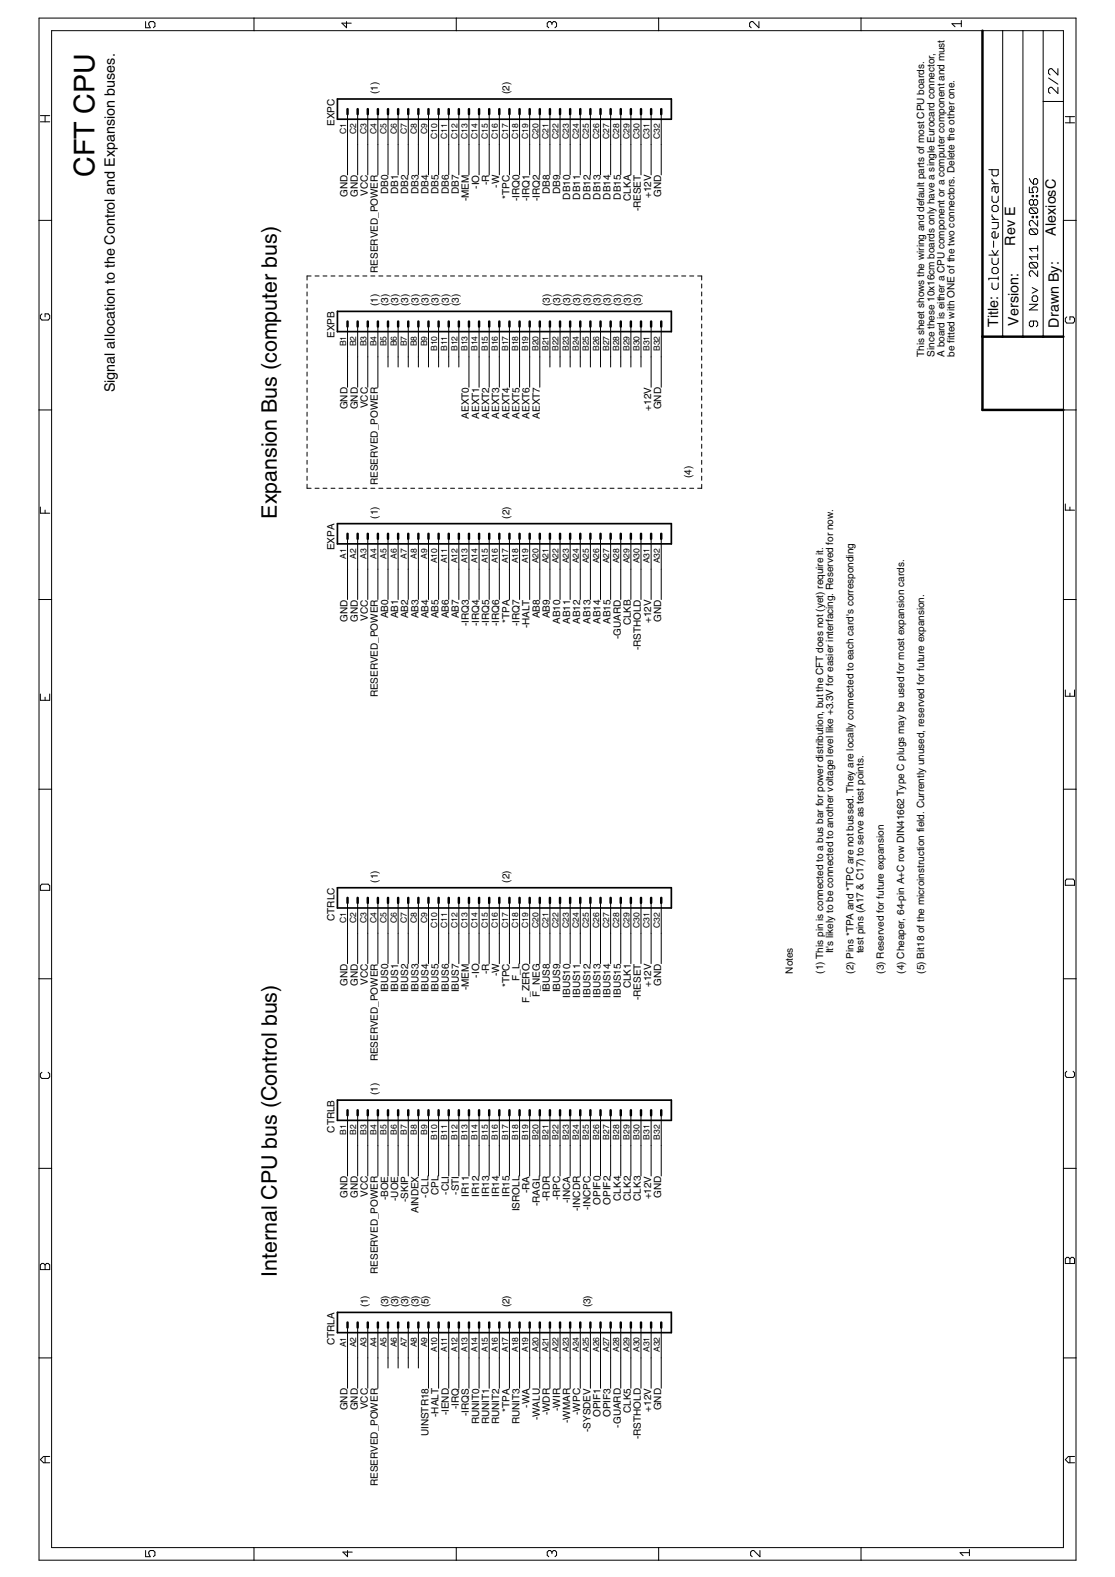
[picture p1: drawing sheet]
<svg xmlns="http://www.w3.org/2000/svg" width="210mm" height="297mm" viewBox="0 0 210 297" stroke-linecap="round" stroke-linejoin="round" font-family="sans-serif">
<defs><g id="words">
<text font-size="5.4" x="17.8" y="33.3" transform="rotate(-90 17.8 33.3)">CFT CPU</text>
<g font-size="4">
<text x="52.1" y="97.7" transform="rotate(-90 52.1 97.7)">Expansion Bus (computer bus)</text>
<text x="52.1" y="240.5" transform="rotate(-90 52.1 240.5)">Internal CPU bus (Control bus)</text>
</g>
<g font-size="2.7">
<text x="191.1" y="46.3" transform="rotate(-90 191.1 46.3)">Rev E</text>
<text x="198.8" y="44.4" transform="rotate(-90 198.8 44.4)">AlexiosC</text>
<text x="187.9" y="61.5" transform="rotate(-90 187.9 61.5)">Title:</text>
<text x="191.7" y="61.3" transform="rotate(-90 191.7 61.3)">Version:</text>
<text x="199.3" y="61.7" transform="rotate(-90 199.3 61.7)">Drawn By:</text>
<text x="21.6" y="73.9" transform="rotate(-90 21.6 73.9)">Signal allocation to the Control and Expansion buses.</text>
</g>
<g font-size="1.9">
<text x="71.1" y="17.7" transform="rotate(-90 71.1 17.7)">(1)</text>
<text x="95.9" y="17.7" transform="rotate(-90 95.9 17.7)">(2)</text>
<text x="63" y="23.7" transform="rotate(-90 63 23.7)">EXPC</text>
<text x="90.2" y="35.6" transform="rotate(-90 90.2 35.6)">-IO</text>
<text x="92.1" y="34.9" transform="rotate(-90 92.1 34.9)">-R</text>
<text x="94" y="35.3" transform="rotate(-90 94 35.3)">-W</text>
<text x="65.4" y="37.1" transform="rotate(-90 65.4 37.1)">GND</text>
<text x="67.3" y="37.1" transform="rotate(-90 67.3 37.1)">GND</text>
<text x="69.2" y="36.9" transform="rotate(-90 69.2 36.9)">VCC</text>
<text x="73" y="36.6" transform="rotate(-90 73 36.6)">DB0</text>
<text x="75" y="36.6" transform="rotate(-90 75 36.6)">DB1</text>
<text x="76.9" y="36.6" transform="rotate(-90 76.9 36.6)">DB2</text>
<text x="78.8" y="36.6" transform="rotate(-90 78.8 36.6)">DB3</text>
<text x="80.7" y="36.6" transform="rotate(-90 80.7 36.6)">DB4</text>
<text x="82.6" y="36.6" transform="rotate(-90 82.6 36.6)">DB5</text>
<text x="84.5" y="36.6" transform="rotate(-90 84.5 36.6)">DB6</text>
<text x="86.4" y="36.6" transform="rotate(-90 86.4 36.6)">DB7</text>
<text x="88.3" y="37.9" transform="rotate(-90 88.3 37.9)">-MEM</text>
<text x="95.9" y="37.4" transform="rotate(-90 95.9 37.4)">*TPC</text>
<text x="97.8" y="37.9" transform="rotate(-90 97.8 37.9)">-IRQ0</text>
<text x="99.7" y="37.9" transform="rotate(-90 99.7 37.9)">-IRQ1</text>
<text x="101.6" y="37.9" transform="rotate(-90 101.6 37.9)">-IRQ2</text>
<text x="103.5" y="36.6" transform="rotate(-90 103.5 36.6)">DB8</text>
<text x="105.4" y="36.6" transform="rotate(-90 105.4 36.6)">DB9</text>
<text x="107.3" y="37.6" transform="rotate(-90 107.3 37.6)">DB10</text>
<text x="109.2" y="37.6" transform="rotate(-90 109.2 37.6)">DB11</text>
<text x="111.1" y="37.6" transform="rotate(-90 111.1 37.6)">DB12</text>
<text x="113" y="37.6" transform="rotate(-90 113 37.6)">DB13</text>
<text x="114.9" y="37.6" transform="rotate(-90 114.9 37.6)">DB14</text>
<text x="116.9" y="37.6" transform="rotate(-90 116.9 37.6)">DB15</text>
<text x="118.8" y="37.8" transform="rotate(-90 118.8 37.8)">CLKA</text>
<text x="120.7" y="39.8" transform="rotate(-90 120.7 39.8)">-RESET</text>
<text x="122.6" y="37.4" transform="rotate(-90 122.6 37.4)">+12V</text>
<text x="124.5" y="37.1" transform="rotate(-90 124.5 37.1)">GND</text>
<text x="71.1" y="51.4" transform="rotate(-90 71.1 51.4)">RESERVED_POWER</text>
<text x="71.1" y="57.7" transform="rotate(-90 71.1 57.7)">(1)</text>
<text x="73" y="57.7" transform="rotate(-90 73 57.7)">(3)</text>
<text x="75" y="57.7" transform="rotate(-90 75 57.7)">(3)</text>
<text x="76.9" y="57.7" transform="rotate(-90 76.9 57.7)">(3)</text>
<text x="78.8" y="57.7" transform="rotate(-90 78.8 57.7)">(3)</text>
<text x="80.7" y="57.7" transform="rotate(-90 80.7 57.7)">(3)</text>
<text x="82.6" y="57.7" transform="rotate(-90 82.6 57.7)">(3)</text>
<text x="84.5" y="57.7" transform="rotate(-90 84.5 57.7)">(3)</text>
<text x="86.4" y="57.7" transform="rotate(-90 86.4 57.7)">(3)</text>
<text x="103.5" y="57.7" transform="rotate(-90 103.5 57.7)">(3)</text>
<text x="105.4" y="57.7" transform="rotate(-90 105.4 57.7)">(3)</text>
<text x="107.3" y="57.7" transform="rotate(-90 107.3 57.7)">(3)</text>
<text x="109.2" y="57.7" transform="rotate(-90 109.2 57.7)">(3)</text>
<text x="111.1" y="57.7" transform="rotate(-90 111.1 57.7)">(3)</text>
<text x="113" y="57.7" transform="rotate(-90 113 57.7)">(3)</text>
<text x="114.9" y="57.7" transform="rotate(-90 114.9 57.7)">(3)</text>
<text x="116.9" y="57.7" transform="rotate(-90 116.9 57.7)">(3)</text>
<text x="118.8" y="57.7" transform="rotate(-90 118.8 57.7)">(3)</text>
<text x="120.7" y="57.7" transform="rotate(-90 120.7 57.7)">(3)</text>
<text x="63" y="63.6" transform="rotate(-90 63 63.6)">EXPB</text>
<text x="174" y="67.2" transform="rotate(-90 174 67.2)">This sheet shows the wiring and default parts of most CPU boards.</text>
<text x="175.9" y="67.2" transform="rotate(-90 175.9 67.2)">Since these 10x16cm boards only have a single Eurocard connector,</text>
<text x="177.8" y="67.2" transform="rotate(-90 177.8 67.2)">A board is either a CPU component or a computer component and must</text>
<text x="179.7" y="67.2" transform="rotate(-90 179.7 67.2)">be fitted with ONE of the two connectors. Delete the other one.</text>
<text x="65.4" y="77.1" transform="rotate(-90 65.4 77.1)">GND</text>
<text x="67.3" y="77.1" transform="rotate(-90 67.3 77.1)">GND</text>
<text x="69.2" y="76.9" transform="rotate(-90 69.2 76.9)">VCC</text>
<text x="122.6" y="77.4" transform="rotate(-90 122.6 77.4)">+12V</text>
<text x="124.5" y="77.1" transform="rotate(-90 124.5 77.1)">GND</text>
<text x="88.3" y="78.9" transform="rotate(-90 88.3 78.9)">AEXT0</text>
<text x="90.2" y="78.9" transform="rotate(-90 90.2 78.9)">AEXT1</text>
<text x="92.1" y="78.9" transform="rotate(-90 92.1 78.9)">AEXT2</text>
<text x="94" y="78.9" transform="rotate(-90 94 78.9)">AEXT3</text>
<text x="95.9" y="78.9" transform="rotate(-90 95.9 78.9)">AEXT4</text>
<text x="97.8" y="78.9" transform="rotate(-90 97.8 78.9)">AEXT5</text>
<text x="99.7" y="78.9" transform="rotate(-90 99.7 78.9)">AEXT6</text>
<text x="101.6" y="78.9" transform="rotate(-90 101.6 78.9)">AEXT7</text>
<text x="71.1" y="91.4" transform="rotate(-90 71.1 91.4)">RESERVED_POWER</text>
<text x="130.2" y="90.1" transform="rotate(-90 130.2 90.1)">(4)</text>
<text x="71.1" y="97.7" transform="rotate(-90 71.1 97.7)">(1)</text>
<text x="95.9" y="97.7" transform="rotate(-90 95.9 97.7)">(2)</text>
<text x="63" y="103.6" transform="rotate(-90 63 103.6)">EXPA</text>
<text x="65.4" y="117.1" transform="rotate(-90 65.4 117.1)">GND</text>
<text x="67.3" y="117.1" transform="rotate(-90 67.3 117.1)">GND</text>
<text x="69.2" y="116.9" transform="rotate(-90 69.2 116.9)">VCC</text>
<text x="73" y="116.5" transform="rotate(-90 73 116.5)">AB0</text>
<text x="75" y="116.5" transform="rotate(-90 75 116.5)">AB1</text>
<text x="76.9" y="116.5" transform="rotate(-90 76.9 116.5)">AB2</text>
<text x="78.8" y="116.5" transform="rotate(-90 78.8 116.5)">AB3</text>
<text x="80.7" y="116.5" transform="rotate(-90 80.7 116.5)">AB4</text>
<text x="82.6" y="116.5" transform="rotate(-90 82.6 116.5)">AB5</text>
<text x="84.5" y="116.5" transform="rotate(-90 84.5 116.5)">AB6</text>
<text x="86.4" y="116.5" transform="rotate(-90 86.4 116.5)">AB7</text>
<text x="88.3" y="117.9" transform="rotate(-90 88.3 117.9)">-IRQ3</text>
<text x="90.2" y="117.9" transform="rotate(-90 90.2 117.9)">-IRQ4</text>
<text x="92.1" y="117.9" transform="rotate(-90 92.1 117.9)">-IRQ5</text>
<text x="94" y="117.9" transform="rotate(-90 94 117.9)">-IRQ6</text>
<text x="95.9" y="117.3" transform="rotate(-90 95.9 117.3)">*TPA</text>
<text x="97.8" y="117.9" transform="rotate(-90 97.8 117.9)">-IRQ7</text>
<text x="99.7" y="118.3" transform="rotate(-90 99.7 118.3)">-HALT</text>
<text x="101.6" y="116.5" transform="rotate(-90 101.6 116.5)">AB8</text>
<text x="103.5" y="116.5" transform="rotate(-90 103.5 116.5)">AB9</text>
<text x="105.4" y="117.5" transform="rotate(-90 105.4 117.5)">AB10</text>
<text x="107.3" y="117.5" transform="rotate(-90 107.3 117.5)">AB11</text>
<text x="109.2" y="117.5" transform="rotate(-90 109.2 117.5)">AB12</text>
<text x="111.1" y="117.5" transform="rotate(-90 111.1 117.5)">AB13</text>
<text x="113" y="117.5" transform="rotate(-90 113 117.5)">AB14</text>
<text x="114.9" y="117.5" transform="rotate(-90 114.9 117.5)">AB15</text>
<text x="118.8" y="117.8" transform="rotate(-90 118.8 117.8)">CLKB</text>
<text x="122.6" y="117.4" transform="rotate(-90 122.6 117.4)">+12V</text>
<text x="124.5" y="117.1" transform="rotate(-90 124.5 117.1)">GND</text>
<text x="116.9" y="120.3" transform="rotate(-90 116.9 120.3)">-GUARD</text>
<text x="120.7" y="122.5" transform="rotate(-90 120.7 122.5)">-RSTHOLD</text>
<text x="71.1" y="131.4" transform="rotate(-90 71.1 131.4)">RESERVED_POWER</text>
<text x="71.1" y="166.3" transform="rotate(-90 71.1 166.3)">(1)</text>
<text x="95.9" y="166.3" transform="rotate(-90 95.9 166.3)">(2)</text>
<text x="63" y="173.5" transform="rotate(-90 63 173.5)">CTRLC</text>
<text x="156.9" y="179.6" transform="rotate(-90 156.9 179.6)">It's likely to be connected to another voltage level like +3.3V for easier interfacing. Reserved for now.</text>
<text x="162.6" y="179.6" transform="rotate(-90 162.6 179.6)">test pins (A17 &amp; C17) to serve as test points.</text>
<text x="65.4" y="185.7" transform="rotate(-90 65.4 185.7)">GND</text>
<text x="67.3" y="185.7" transform="rotate(-90 67.3 185.7)">GND</text>
<text x="69.2" y="185.5" transform="rotate(-90 69.2 185.5)">VCC</text>
<text x="90.2" y="184.1" transform="rotate(-90 90.2 184.1)">-IO</text>
<text x="92.1" y="183.5" transform="rotate(-90 92.1 183.5)">-R</text>
<text x="94" y="183.9" transform="rotate(-90 94 183.9)">-W</text>
<text x="95.9" y="186" transform="rotate(-90 95.9 186)">*TPC</text>
<text x="97.8" y="184.7" transform="rotate(-90 97.8 184.7)">F_L</text>
<text x="122.6" y="185.9" transform="rotate(-90 122.6 185.9)">+12V</text>
<text x="124.5" y="185.7" transform="rotate(-90 124.5 185.7)">GND</text>
<text x="149.2" y="183.4" transform="rotate(-90 149.2 183.4)">Notes</text>
<text x="154.9" y="183.4" transform="rotate(-90 154.9 183.4)">(1) This pin is connected to a bus bar for power distribution, but the CFT does not (yet) require it.</text>
<text x="160.7" y="183.4" transform="rotate(-90 160.7 183.4)">(2) Pins *TPA and *TPC are not bussed. They are locally connected to each card's corresponding</text>
<text x="166.4" y="183.4" transform="rotate(-90 166.4 183.4)">(3) Reserved for future expansion</text>
<text x="170.2" y="183.4" transform="rotate(-90 170.2 183.4)">(4) Cheaper, 64-pin A+C row DIN41662 Type C plugs may be used for most expansion cards.</text>
<text x="174" y="183.4" transform="rotate(-90 174 183.4)">(5) Bit18 of the microinstruction field. Currently unused, reserved for future expansion.</text>
<text x="73" y="186.9" transform="rotate(-90 73 186.9)">IBUS0</text>
<text x="75" y="186.9" transform="rotate(-90 75 186.9)">IBUS1</text>
<text x="76.9" y="186.9" transform="rotate(-90 76.9 186.9)">IBUS2</text>
<text x="78.8" y="186.9" transform="rotate(-90 78.8 186.9)">IBUS3</text>
<text x="80.7" y="186.9" transform="rotate(-90 80.7 186.9)">IBUS4</text>
<text x="82.6" y="186.9" transform="rotate(-90 82.6 186.9)">IBUS5</text>
<text x="84.5" y="186.9" transform="rotate(-90 84.5 186.9)">IBUS6</text>
<text x="86.4" y="186.9" transform="rotate(-90 86.4 186.9)">IBUS7</text>
<text x="88.3" y="186.5" transform="rotate(-90 88.3 186.5)">-MEM</text>
<text x="99.7" y="188.9" transform="rotate(-90 99.7 188.9)">F_ZERO</text>
<text x="101.6" y="187.7" transform="rotate(-90 101.6 187.7)">F_NEG</text>
<text x="103.5" y="186.9" transform="rotate(-90 103.5 186.9)">IBUS8</text>
<text x="105.4" y="186.9" transform="rotate(-90 105.4 186.9)">IBUS9</text>
<text x="107.3" y="188" transform="rotate(-90 107.3 188)">IBUS10</text>
<text x="109.2" y="188" transform="rotate(-90 109.2 188)">IBUS11</text>
<text x="111.1" y="188" transform="rotate(-90 111.1 188)">IBUS12</text>
<text x="113" y="188" transform="rotate(-90 113 188)">IBUS13</text>
<text x="114.9" y="188" transform="rotate(-90 114.9 188)">IBUS14</text>
<text x="116.9" y="188" transform="rotate(-90 116.9 188)">IBUS15</text>
<text x="118.8" y="186.2" transform="rotate(-90 118.8 186.2)">CLK1</text>
<text x="120.7" y="188.4" transform="rotate(-90 120.7 188.4)">-RESET</text>
<text x="71.1" y="199.9" transform="rotate(-90 71.1 199.9)">RESERVED_POWER</text>
<text x="71.1" y="206.3" transform="rotate(-90 71.1 206.3)">(1)</text>
<text x="63" y="213.3" transform="rotate(-90 63 213.3)">CTRLB</text>
<text x="65.4" y="225.7" transform="rotate(-90 65.4 225.7)">GND</text>
<text x="67.3" y="225.7" transform="rotate(-90 67.3 225.7)">GND</text>
<text x="69.2" y="225.5" transform="rotate(-90 69.2 225.5)">VCC</text>
<text x="73" y="226.1" transform="rotate(-90 73 226.1)">-BOE</text>
<text x="75" y="226.2" transform="rotate(-90 75 226.2)">-UOE</text>
<text x="76.9" y="226.4" transform="rotate(-90 76.9 226.4)">-SKIP</text>
<text x="80.7" y="225.6" transform="rotate(-90 80.7 225.6)">-CLL</text>
<text x="82.6" y="225.1" transform="rotate(-90 82.6 225.1)">CPL</text>
<text x="84.5" y="225.1" transform="rotate(-90 84.5 225.1)">-CLI</text>
<text x="86.4" y="225.1" transform="rotate(-90 86.4 225.1)">-STI</text>
<text x="88.3" y="225.5" transform="rotate(-90 88.3 225.5)">IR11</text>
<text x="90.2" y="225.5" transform="rotate(-90 90.2 225.5)">IR12</text>
<text x="92.1" y="225.5" transform="rotate(-90 92.1 225.5)">IR13</text>
<text x="94" y="225.5" transform="rotate(-90 94 225.5)">IR14</text>
<text x="95.9" y="225.5" transform="rotate(-90 95.9 225.5)">IR15</text>
<text x="99.7" y="224.7" transform="rotate(-90 99.7 224.7)">-RA</text>
<text x="101.6" y="227.2" transform="rotate(-90 101.6 227.2)">-RAGL</text>
<text x="103.5" y="226.2" transform="rotate(-90 103.5 226.2)">-RDR</text>
<text x="105.4" y="226.1" transform="rotate(-90 105.4 226.1)">-RPC</text>
<text x="107.3" y="226.6" transform="rotate(-90 107.3 226.6)">-INCA</text>
<text x="111.1" y="228" transform="rotate(-90 111.1 228)">-INCPC</text>
<text x="113" y="226.9" transform="rotate(-90 113 226.9)">OPIF0</text>
<text x="114.9" y="226.9" transform="rotate(-90 114.9 226.9)">OPIF2</text>
<text x="116.9" y="226.2" transform="rotate(-90 116.9 226.2)">CLK4</text>
<text x="118.8" y="226.2" transform="rotate(-90 118.8 226.2)">CLK2</text>
<text x="120.7" y="226.2" transform="rotate(-90 120.7 226.2)">CLK3</text>
<text x="122.6" y="225.9" transform="rotate(-90 122.6 225.9)">+12V</text>
<text x="124.5" y="225.7" transform="rotate(-90 124.5 225.7)">GND</text>
<text x="78.8" y="228.5" transform="rotate(-90 78.8 228.5)">AINDEX</text>
<text x="97.8" y="228.2" transform="rotate(-90 97.8 228.2)">ISROLL</text>
<text x="109.2" y="228.1" transform="rotate(-90 109.2 228.1)">-INCDR</text>
<text x="71.1" y="239.9" transform="rotate(-90 71.1 239.9)">RESERVED_POWER</text>
<text x="69.2" y="246.3" transform="rotate(-90 69.2 246.3)">(1)</text>
<text x="73" y="246.3" transform="rotate(-90 73 246.3)">(3)</text>
<text x="75" y="246.3" transform="rotate(-90 75 246.3)">(3)</text>
<text x="76.9" y="246.3" transform="rotate(-90 76.9 246.3)">(3)</text>
<text x="78.8" y="246.3" transform="rotate(-90 78.8 246.3)">(3)</text>
<text x="80.7" y="246.3" transform="rotate(-90 80.7 246.3)">(5)</text>
<text x="95.9" y="246.3" transform="rotate(-90 95.9 246.3)">(2)</text>
<text x="111.1" y="246.3" transform="rotate(-90 111.1 246.3)">(3)</text>
<text x="63" y="253.3" transform="rotate(-90 63 253.3)">CTRLA</text>
<text x="65.4" y="265.7" transform="rotate(-90 65.4 265.7)">GND</text>
<text x="67.3" y="265.7" transform="rotate(-90 67.3 265.7)">GND</text>
<text x="69.2" y="265.5" transform="rotate(-90 69.2 265.5)">VCC</text>
<text x="82.6" y="266.9" transform="rotate(-90 82.6 266.9)">-HALT</text>
<text x="84.5" y="266.6" transform="rotate(-90 84.5 266.6)">-IEND</text>
<text x="86.4" y="265.5" transform="rotate(-90 86.4 265.5)">-IRQ</text>
<text x="88.3" y="266.7" transform="rotate(-90 88.3 266.7)">-IRQS</text>
<text x="90.2" y="268.3" transform="rotate(-90 90.2 268.3)">RUNIT0</text>
<text x="92.1" y="268.3" transform="rotate(-90 92.1 268.3)">RUNIT1</text>
<text x="94" y="268.3" transform="rotate(-90 94 268.3)">RUNIT2</text>
<text x="95.9" y="265.9" transform="rotate(-90 95.9 265.9)">*TPA</text>
<text x="97.8" y="268.3" transform="rotate(-90 97.8 268.3)">RUNIT3</text>
<text x="99.7" y="265.2" transform="rotate(-90 99.7 265.2)">-WA</text>
<text x="101.6" y="267.5" transform="rotate(-90 101.6 267.5)">-WALU</text>
<text x="103.5" y="266.6" transform="rotate(-90 103.5 266.6)">-WDR</text>
<text x="105.4" y="265.8" transform="rotate(-90 105.4 265.8)">-WIR</text>
<text x="107.3" y="268.1" transform="rotate(-90 107.3 268.1)">-WMAR</text>
<text x="109.2" y="266.5" transform="rotate(-90 109.2 266.5)">-WPC</text>
<text x="111.1" y="269.7" transform="rotate(-90 111.1 269.7)">-SYSDEV</text>
<text x="113" y="266.9" transform="rotate(-90 113 266.9)">OPIF1</text>
<text x="114.9" y="266.9" transform="rotate(-90 114.9 266.9)">OPIF3</text>
<text x="116.9" y="268.9" transform="rotate(-90 116.9 268.9)">-GUARD</text>
<text x="118.8" y="266.2" transform="rotate(-90 118.8 266.2)">CLK5</text>
<text x="122.6" y="265.9" transform="rotate(-90 122.6 265.9)">+12V</text>
<text x="124.5" y="265.7" transform="rotate(-90 124.5 265.7)">GND</text>
<text x="80.7" y="270.6" transform="rotate(-90 80.7 270.6)">UINSTR18</text>
<text x="120.7" y="271.1" transform="rotate(-90 120.7 271.1)">-RSTHOLD</text>
<text x="71.1" y="279.9" transform="rotate(-90 71.1 279.9)">RESERVED_POWER</text>
</g>
<g font-size="1.6">
<text x="65.2" y="25.3" transform="rotate(-90 65.2 25.3)">C1</text>
<text x="67.1" y="25.3" transform="rotate(-90 67.1 25.3)">C2</text>
<text x="69" y="25.3" transform="rotate(-90 69 25.3)">C3</text>
<text x="70.9" y="25.3" transform="rotate(-90 70.9 25.3)">C4</text>
<text x="72.8" y="25.3" transform="rotate(-90 72.8 25.3)">C5</text>
<text x="74.7" y="25.3" transform="rotate(-90 74.7 25.3)">C6</text>
<text x="76.6" y="25.3" transform="rotate(-90 76.6 25.3)">C7</text>
<text x="78.5" y="25.3" transform="rotate(-90 78.5 25.3)">C8</text>
<text x="80.4" y="25.3" transform="rotate(-90 80.4 25.3)">C9</text>
<text x="82.3" y="26.2" transform="rotate(-90 82.3 26.2)">C10</text>
<text x="84.2" y="26.2" transform="rotate(-90 84.2 26.2)">C11</text>
<text x="86.1" y="26.2" transform="rotate(-90 86.1 26.2)">C12</text>
<text x="88" y="26.2" transform="rotate(-90 88 26.2)">C13</text>
<text x="89.9" y="26.2" transform="rotate(-90 89.9 26.2)">C14</text>
<text x="91.8" y="26.2" transform="rotate(-90 91.8 26.2)">C15</text>
<text x="93.7" y="26.2" transform="rotate(-90 93.7 26.2)">C16</text>
<text x="95.6" y="26.2" transform="rotate(-90 95.6 26.2)">C17</text>
<text x="97.5" y="26.2" transform="rotate(-90 97.5 26.2)">C18</text>
<text x="99.4" y="26.2" transform="rotate(-90 99.4 26.2)">C19</text>
<text x="101.3" y="26.2" transform="rotate(-90 101.3 26.2)">C20</text>
<text x="103.3" y="26.2" transform="rotate(-90 103.3 26.2)">C21</text>
<text x="105.2" y="26.2" transform="rotate(-90 105.2 26.2)">C22</text>
<text x="107.1" y="26.2" transform="rotate(-90 107.1 26.2)">C23</text>
<text x="109" y="26.2" transform="rotate(-90 109 26.2)">C24</text>
<text x="110.9" y="26.2" transform="rotate(-90 110.9 26.2)">C25</text>
<text x="112.8" y="26.2" transform="rotate(-90 112.8 26.2)">C26</text>
<text x="114.7" y="26.2" transform="rotate(-90 114.7 26.2)">C27</text>
<text x="116.6" y="26.2" transform="rotate(-90 116.6 26.2)">C28</text>
<text x="118.5" y="26.2" transform="rotate(-90 118.5 26.2)">C29</text>
<text x="120.4" y="26.2" transform="rotate(-90 120.4 26.2)">C30</text>
<text x="122.3" y="26.2" transform="rotate(-90 122.3 26.2)">C31</text>
<text x="124.2" y="26.2" transform="rotate(-90 124.2 26.2)">C32</text>
<text x="65.2" y="65.2" transform="rotate(-90 65.2 65.2)">B1</text>
<text x="67.1" y="65.2" transform="rotate(-90 67.1 65.2)">B2</text>
<text x="69" y="65.2" transform="rotate(-90 69 65.2)">B3</text>
<text x="70.9" y="65.2" transform="rotate(-90 70.9 65.2)">B4</text>
<text x="72.8" y="65.2" transform="rotate(-90 72.8 65.2)">B5</text>
<text x="74.7" y="65.2" transform="rotate(-90 74.7 65.2)">B6</text>
<text x="76.6" y="65.2" transform="rotate(-90 76.6 65.2)">B7</text>
<text x="78.5" y="65.2" transform="rotate(-90 78.5 65.2)">B8</text>
<text x="80.4" y="65.2" transform="rotate(-90 80.4 65.2)">B9</text>
<text x="82.3" y="66.1" transform="rotate(-90 82.3 66.1)">B10</text>
<text x="84.2" y="66.1" transform="rotate(-90 84.2 66.1)">B11</text>
<text x="86.1" y="66.1" transform="rotate(-90 86.1 66.1)">B12</text>
<text x="88" y="66.1" transform="rotate(-90 88 66.1)">B13</text>
<text x="89.9" y="66.1" transform="rotate(-90 89.9 66.1)">B14</text>
<text x="91.8" y="66.1" transform="rotate(-90 91.8 66.1)">B15</text>
<text x="93.7" y="66.1" transform="rotate(-90 93.7 66.1)">B16</text>
<text x="95.6" y="66.1" transform="rotate(-90 95.6 66.1)">B17</text>
<text x="97.5" y="66.1" transform="rotate(-90 97.5 66.1)">B18</text>
<text x="99.4" y="66.1" transform="rotate(-90 99.4 66.1)">B19</text>
<text x="101.3" y="66.1" transform="rotate(-90 101.3 66.1)">B20</text>
<text x="103.3" y="66.1" transform="rotate(-90 103.3 66.1)">B21</text>
<text x="105.2" y="66.1" transform="rotate(-90 105.2 66.1)">B22</text>
<text x="107.1" y="66.1" transform="rotate(-90 107.1 66.1)">B23</text>
<text x="109" y="66.1" transform="rotate(-90 109 66.1)">B24</text>
<text x="110.9" y="66.1" transform="rotate(-90 110.9 66.1)">B25</text>
<text x="112.8" y="66.1" transform="rotate(-90 112.8 66.1)">B26</text>
<text x="114.7" y="66.1" transform="rotate(-90 114.7 66.1)">B27</text>
<text x="116.6" y="66.1" transform="rotate(-90 116.6 66.1)">B28</text>
<text x="118.5" y="66.1" transform="rotate(-90 118.5 66.1)">B29</text>
<text x="120.4" y="66.1" transform="rotate(-90 120.4 66.1)">B30</text>
<text x="122.3" y="66.1" transform="rotate(-90 122.3 66.1)">B31</text>
<text x="124.2" y="66.1" transform="rotate(-90 124.2 66.1)">B32</text>
<text x="65.2" y="105.2" transform="rotate(-90 65.2 105.2)">A1</text>
<text x="67.1" y="105.2" transform="rotate(-90 67.1 105.2)">A2</text>
<text x="69" y="105.2" transform="rotate(-90 69 105.2)">A3</text>
<text x="70.9" y="105.2" transform="rotate(-90 70.9 105.2)">A4</text>
<text x="72.8" y="105.2" transform="rotate(-90 72.8 105.2)">A5</text>
<text x="74.7" y="105.2" transform="rotate(-90 74.7 105.2)">A6</text>
<text x="76.6" y="105.2" transform="rotate(-90 76.6 105.2)">A7</text>
<text x="78.5" y="105.2" transform="rotate(-90 78.5 105.2)">A8</text>
<text x="80.4" y="105.2" transform="rotate(-90 80.4 105.2)">A9</text>
<text x="82.3" y="106.1" transform="rotate(-90 82.3 106.1)">A10</text>
<text x="84.2" y="106.1" transform="rotate(-90 84.2 106.1)">A11</text>
<text x="86.1" y="106.1" transform="rotate(-90 86.1 106.1)">A12</text>
<text x="88" y="106.1" transform="rotate(-90 88 106.1)">A13</text>
<text x="89.9" y="106.1" transform="rotate(-90 89.9 106.1)">A14</text>
<text x="91.8" y="106.1" transform="rotate(-90 91.8 106.1)">A15</text>
<text x="93.7" y="106.1" transform="rotate(-90 93.7 106.1)">A16</text>
<text x="95.6" y="106.1" transform="rotate(-90 95.6 106.1)">A17</text>
<text x="97.5" y="106.1" transform="rotate(-90 97.5 106.1)">A18</text>
<text x="99.4" y="106.1" transform="rotate(-90 99.4 106.1)">A19</text>
<text x="101.3" y="106.1" transform="rotate(-90 101.3 106.1)">A20</text>
<text x="103.3" y="106.1" transform="rotate(-90 103.3 106.1)">A21</text>
<text x="105.2" y="106.1" transform="rotate(-90 105.2 106.1)">A22</text>
<text x="107.1" y="106.1" transform="rotate(-90 107.1 106.1)">A23</text>
<text x="109" y="106.1" transform="rotate(-90 109 106.1)">A24</text>
<text x="110.9" y="106.1" transform="rotate(-90 110.9 106.1)">A25</text>
<text x="112.8" y="106.1" transform="rotate(-90 112.8 106.1)">A26</text>
<text x="114.7" y="106.1" transform="rotate(-90 114.7 106.1)">A27</text>
<text x="116.6" y="106.1" transform="rotate(-90 116.6 106.1)">A28</text>
<text x="118.5" y="106.1" transform="rotate(-90 118.5 106.1)">A29</text>
<text x="120.4" y="106.1" transform="rotate(-90 120.4 106.1)">A30</text>
<text x="122.3" y="106.1" transform="rotate(-90 122.3 106.1)">A31</text>
<text x="124.2" y="106.1" transform="rotate(-90 124.2 106.1)">A32</text>
<text x="65.2" y="173.9" transform="rotate(-90 65.2 173.9)">C1</text>
<text x="67.1" y="173.9" transform="rotate(-90 67.1 173.9)">C2</text>
<text x="69" y="173.9" transform="rotate(-90 69 173.9)">C3</text>
<text x="70.9" y="173.9" transform="rotate(-90 70.9 173.9)">C4</text>
<text x="72.8" y="173.9" transform="rotate(-90 72.8 173.9)">C5</text>
<text x="74.7" y="173.9" transform="rotate(-90 74.7 173.9)">C6</text>
<text x="76.6" y="173.9" transform="rotate(-90 76.6 173.9)">C7</text>
<text x="78.5" y="173.9" transform="rotate(-90 78.5 173.9)">C8</text>
<text x="80.4" y="173.9" transform="rotate(-90 80.4 173.9)">C9</text>
<text x="82.3" y="174.8" transform="rotate(-90 82.3 174.8)">C10</text>
<text x="84.2" y="174.8" transform="rotate(-90 84.2 174.8)">C11</text>
<text x="86.1" y="174.8" transform="rotate(-90 86.1 174.8)">C12</text>
<text x="88" y="174.8" transform="rotate(-90 88 174.8)">C13</text>
<text x="89.9" y="174.8" transform="rotate(-90 89.9 174.8)">C14</text>
<text x="91.8" y="174.8" transform="rotate(-90 91.8 174.8)">C15</text>
<text x="93.7" y="174.8" transform="rotate(-90 93.7 174.8)">C16</text>
<text x="95.6" y="174.8" transform="rotate(-90 95.6 174.8)">C17</text>
<text x="97.5" y="174.8" transform="rotate(-90 97.5 174.8)">C18</text>
<text x="99.4" y="174.8" transform="rotate(-90 99.4 174.8)">C19</text>
<text x="101.3" y="174.8" transform="rotate(-90 101.3 174.8)">C20</text>
<text x="103.3" y="174.8" transform="rotate(-90 103.3 174.8)">C21</text>
<text x="105.2" y="174.8" transform="rotate(-90 105.2 174.8)">C22</text>
<text x="107.1" y="174.8" transform="rotate(-90 107.1 174.8)">C23</text>
<text x="109" y="174.8" transform="rotate(-90 109 174.8)">C24</text>
<text x="110.9" y="174.8" transform="rotate(-90 110.9 174.8)">C25</text>
<text x="112.8" y="174.8" transform="rotate(-90 112.8 174.8)">C26</text>
<text x="114.7" y="174.8" transform="rotate(-90 114.7 174.8)">C27</text>
<text x="116.6" y="174.8" transform="rotate(-90 116.6 174.8)">C28</text>
<text x="118.5" y="174.8" transform="rotate(-90 118.5 174.8)">C29</text>
<text x="120.4" y="174.8" transform="rotate(-90 120.4 174.8)">C30</text>
<text x="122.3" y="174.8" transform="rotate(-90 122.3 174.8)">C31</text>
<text x="124.2" y="174.8" transform="rotate(-90 124.2 174.8)">C32</text>
<text x="65.2" y="213.8" transform="rotate(-90 65.2 213.8)">B1</text>
<text x="67.1" y="213.8" transform="rotate(-90 67.1 213.8)">B2</text>
<text x="69" y="213.8" transform="rotate(-90 69 213.8)">B3</text>
<text x="70.9" y="213.8" transform="rotate(-90 70.9 213.8)">B4</text>
<text x="72.8" y="213.8" transform="rotate(-90 72.8 213.8)">B5</text>
<text x="74.7" y="213.8" transform="rotate(-90 74.7 213.8)">B6</text>
<text x="76.6" y="213.8" transform="rotate(-90 76.6 213.8)">B7</text>
<text x="78.5" y="213.8" transform="rotate(-90 78.5 213.8)">B8</text>
<text x="80.4" y="213.8" transform="rotate(-90 80.4 213.8)">B9</text>
<text x="82.3" y="214.7" transform="rotate(-90 82.3 214.7)">B10</text>
<text x="84.2" y="214.7" transform="rotate(-90 84.2 214.7)">B11</text>
<text x="86.1" y="214.7" transform="rotate(-90 86.1 214.7)">B12</text>
<text x="88" y="214.7" transform="rotate(-90 88 214.7)">B13</text>
<text x="89.9" y="214.7" transform="rotate(-90 89.9 214.7)">B14</text>
<text x="91.8" y="214.7" transform="rotate(-90 91.8 214.7)">B15</text>
<text x="93.7" y="214.7" transform="rotate(-90 93.7 214.7)">B16</text>
<text x="95.6" y="214.7" transform="rotate(-90 95.6 214.7)">B17</text>
<text x="97.5" y="214.7" transform="rotate(-90 97.5 214.7)">B18</text>
<text x="99.4" y="214.7" transform="rotate(-90 99.4 214.7)">B19</text>
<text x="101.3" y="214.7" transform="rotate(-90 101.3 214.7)">B20</text>
<text x="103.3" y="214.7" transform="rotate(-90 103.3 214.7)">B21</text>
<text x="105.2" y="214.7" transform="rotate(-90 105.2 214.7)">B22</text>
<text x="107.1" y="214.7" transform="rotate(-90 107.1 214.7)">B23</text>
<text x="109" y="214.7" transform="rotate(-90 109 214.7)">B24</text>
<text x="110.9" y="214.7" transform="rotate(-90 110.9 214.7)">B25</text>
<text x="112.8" y="214.7" transform="rotate(-90 112.8 214.7)">B26</text>
<text x="114.7" y="214.7" transform="rotate(-90 114.7 214.7)">B27</text>
<text x="116.6" y="214.7" transform="rotate(-90 116.6 214.7)">B28</text>
<text x="118.5" y="214.7" transform="rotate(-90 118.5 214.7)">B29</text>
<text x="120.4" y="214.7" transform="rotate(-90 120.4 214.7)">B30</text>
<text x="122.3" y="214.7" transform="rotate(-90 122.3 214.7)">B31</text>
<text x="124.2" y="214.7" transform="rotate(-90 124.2 214.7)">B32</text>
<text x="65.2" y="253.8" transform="rotate(-90 65.2 253.8)">A1</text>
<text x="67.1" y="253.8" transform="rotate(-90 67.1 253.8)">A2</text>
<text x="69" y="253.8" transform="rotate(-90 69 253.8)">A3</text>
<text x="70.9" y="253.8" transform="rotate(-90 70.9 253.8)">A4</text>
<text x="72.8" y="253.8" transform="rotate(-90 72.8 253.8)">A5</text>
<text x="74.7" y="253.8" transform="rotate(-90 74.7 253.8)">A6</text>
<text x="76.6" y="253.8" transform="rotate(-90 76.6 253.8)">A7</text>
<text x="78.5" y="253.8" transform="rotate(-90 78.5 253.8)">A8</text>
<text x="80.4" y="253.8" transform="rotate(-90 80.4 253.8)">A9</text>
<text x="82.3" y="254.7" transform="rotate(-90 82.3 254.7)">A10</text>
<text x="84.2" y="254.7" transform="rotate(-90 84.2 254.7)">A11</text>
<text x="86.1" y="254.7" transform="rotate(-90 86.1 254.7)">A12</text>
<text x="88" y="254.7" transform="rotate(-90 88 254.7)">A13</text>
<text x="89.9" y="254.7" transform="rotate(-90 89.9 254.7)">A14</text>
<text x="91.8" y="254.7" transform="rotate(-90 91.8 254.7)">A15</text>
<text x="93.7" y="254.7" transform="rotate(-90 93.7 254.7)">A16</text>
<text x="95.6" y="254.7" transform="rotate(-90 95.6 254.7)">A17</text>
<text x="97.5" y="254.7" transform="rotate(-90 97.5 254.7)">A18</text>
<text x="99.4" y="254.7" transform="rotate(-90 99.4 254.7)">A19</text>
<text x="101.3" y="254.7" transform="rotate(-90 101.3 254.7)">A20</text>
<text x="103.3" y="254.7" transform="rotate(-90 103.3 254.7)">A21</text>
<text x="105.2" y="254.7" transform="rotate(-90 105.2 254.7)">A22</text>
<text x="107.1" y="254.7" transform="rotate(-90 107.1 254.7)">A23</text>
<text x="109" y="254.7" transform="rotate(-90 109 254.7)">A24</text>
<text x="110.9" y="254.7" transform="rotate(-90 110.9 254.7)">A25</text>
<text x="112.8" y="254.7" transform="rotate(-90 112.8 254.7)">A26</text>
<text x="114.7" y="254.7" transform="rotate(-90 114.7 254.7)">A27</text>
<text x="116.6" y="254.7" transform="rotate(-90 116.6 254.7)">A28</text>
<text x="118.5" y="254.7" transform="rotate(-90 118.5 254.7)">A29</text>
<text x="120.4" y="254.7" transform="rotate(-90 120.4 254.7)">A30</text>
<text x="122.3" y="254.7" transform="rotate(-90 122.3 254.7)">A31</text>
<text x="124.2" y="254.7" transform="rotate(-90 124.2 254.7)">A32</text>
</g>
</g></defs>
<g fill="#000" stroke="#000" stroke-width=".19">
<path d="M7.3 3.4v38.1zM9.7 5.8v35.7zM27.4 4.1v1.1zM27.4 5.2h.9zM28 4.4v.3zM28.3 4.1l-.3 .3zM28 4.7l.3 .5zM28.3 4.1h.6zM28.9 4.1l.3 .3zM29.2 4.4v.6zM28.9 5.2l.3-.2zM7.3 3.4h40.5z"/>
<path d="M9.7 5.8h38.1zM47.8 3.4v2.4zM64.4 4.4l.8 .8zM65.2 4.1v1.1zM64.4 4.4h1.7zM47.8 3.4h38.1zM47.8 5.8h38.1zM85.9 3.4v2.4zM103 4.4v.6zM103 4.4l.3-.3zM103 5l.3 .2zM103.3 4.1h.3z"/>
<path d="M103.6 4.1l.3 .3zM103.9 4.4v.3zM103.9 4.4l.3-.3zM104.2 4.1h.3zM104.5 4.1l.3 .3zM104.8 4.4v.6zM104.5 5.2l.3-.2zM85.9 3.4h38.1zM85.9 5.8h38.1zM124 3.4v2.4zM141.1 4.4v.6zM141.1 5l.3 .2z"/>
<path d="M141.1 4.4l.3-.3zM141.4 4.1h.3zM142.9 4.1v1.1zM141.7 4.1l1.2 1.1zM124 3.4h38.1zM124 5.8h38.1zM162.1 3.4v2.4zM179.2 4.5h1.8zM179.2 4.5l.6 .5zM181 3.9v1.1zM162.1 5.8h22.9zM185 5.8h3.8z"/>
<path d="M188.8 5.8h3.8zM192.6 5.8h3.8zM196.4 5.8v13.3zM196.4 19.1v44.3zM197.4 16.7v.6zM197.4 17.3l.3 .3zM197.4 13.2v.6zM197.4 13.8l.3 .3zM197.7 16.4l-.3 .3zM197.7 12.9l-.3 .3zM197.7 16.4h.3zM197.7 12.9h.3z"/>
<path d="M199.2 16.4v1.2zM198 16.4l1.2 1.2zM197.4 14.7l1.8 1.2zM199.2 12.9v1.2zM198 12.9l1.2 1.2zM200.2 5.8v13.3zM196.4 5.8h3.8zM196.4 19.1h3.8zM162.1 3.4h40.5zM7.6 21.8h1.8zM8.5 21.8v1.1zM7.6 22.9h1.8z"/>
<path d="M65.4 21.5v5.7zM65.4 27.2v5.7zM67.3 21.5v5.7zM67.3 27.2v5.7zM69.2 21.5v5.7zM69.2 27.2v5.7zM71.1 21.5v5.7zM71.1 27.2v5.7zM73 21.5v5.7zM73 27.2v5.7zM74.9 21.5v5.7zM74.9 27.2v5.7z"/>
<path d="M76.9 21.5v5.7zM76.9 27.2v5.7zM78.8 21.5v5.7zM78.8 27.2v5.7zM80.7 21.5v5.7zM80.7 27.2v5.7zM82.6 21.5v5.7zM82.6 27.2v5.7zM84.5 21.5v5.7zM84.5 27.2v5.7zM86.4 21.5v5.7zM86.4 27.2v5.7z"/>
<path d="M88.3 21.5v5.7zM88.3 27.2v5.7zM90.2 21.5v5.7zM90.2 27.2v5.7zM92.1 21.5v5.7zM92.1 27.2v5.7zM94 21.5v5.7zM94 27.2v5.7zM95.9 21.5v5.7zM95.9 27.2v5.7zM97.8 21.5v5.7zM97.8 27.2v5.7z"/>
<path d="M99.7 21.5v5.7zM99.7 27.2v5.7zM101.6 21.5v5.7zM101.6 27.2v5.7zM103.5 21.5v5.7zM103.5 27.2v5.7zM105.4 21.5v5.7zM105.4 27.2v5.7zM107.3 21.5v5.7zM107.3 27.2v5.7zM109.2 21.5v5.7zM109.2 27.2v5.7z"/>
<path d="M111.1 21.5v5.7zM111.1 27.2v5.7zM113 21.5v5.7zM113 27.2v5.7zM115 21.5v5.7zM115 27.2v5.7zM116.9 21.5v5.7zM116.9 27.2v5.7zM118.8 21.5v5.7zM118.8 27.2v5.7zM120.7 21.5v5.7zM120.7 27.2v5.7z"/>
<path d="M122.6 21.5v5.7zM122.6 27.2v5.7zM124.5 21.5v5.7zM124.5 27.2v5.7zM186.2 32h1.7zM186.8 39v.6zM186.8 39.6l.2 .3zM186.8 36.9v.9zM186.8 37.8l.2 .3zM186.8 35.5v.6zM186.8 35.5l.2-.3zM186.8 33.7v.3z"/>
<path d="M186.8 32v.9zM187 38.7l-.2 .3zM187 39.9h.6zM187 38.1h.6zM187 35.2h.9zM186.8 32.9l.2 .2zM187.3 35.2v.9zM186.8 34l.5 .6zM187 38.7h.6zM187.6 39.9l.3-.3zM187.6 38.1l.3-.3zM187.3 36.1l.3 .2z"/>
<path d="M187 33.1h.6zM187.9 39v.6zM187.6 38.7l.3 .3zM187.9 36.9v.9zM187.9 35.2v.9zM187.6 36.3l.3-.2zM186.8 34.6h1.1zM187.9 32v.9zM187.6 33.1l.3-.2zM193.8 39.4v.6zM194 39.2l-.2 .2zM193.8 37.8v.6z"/>
<path d="M193.8 37.8l.2-.2zM193.8 35.2v1.1zM193.8 36.3h.8zM193.8 33.6l.2 .6zM194 39.2h1.1zM193.8 38.4l.2 .2zM194 37.6h.3zM194 34.2l.6 .5zM194.3 37.6l.3 .2zM194 38.6h.3zM194.3 36.8v.3zM194.3 36.8h.3z"/>
<path d="M194.3 35.5v.2zM194.6 35.2l-.3 .3zM194.6 37.8l.2-.2zM194.6 38.4l-.3 .2zM194.6 37.8v.6zM194.6 36.8v.3zM194.3 37.1h.3zM194.3 35.7l.3 .6zM194.6 35.2h.5zM194.6 34.7h.5zM194.6 33.9v.8zM194.8 37.6h.3z"/>
<path d="M194.6 38.4l.2 .2zM194.8 33.6l-.2 .3zM195.1 39.2l.2 .2zM195.1 37.6l.2 .2zM194.8 38.6h.3zM195.1 36.8v.3zM195.1 36.8h.2zM195.1 35.2l.2 .3zM195.3 34.4l-.2 .3zM194.8 33.6h.3zM195.3 39.4v.6zM195.3 40l-.2 .2z"/>
<path d="M195.3 37.8v.6zM195.3 38.4l-.2 .2zM195.3 36.8v.3zM195.1 37.1h.2zM195.3 35.5v.5zM195.3 36l-.2 .3zM195.3 33.9v.5zM195.1 33.6l.2 .3zM200.6 22h1.7zM201.4 22v1.1zM200.6 23.1h1.7zM7.3 41.5v35.7z"/>
<path d="M7.3 41.5h2.4zM7.6 59.4v.6zM7.6 60l.3 .3zM7.9 59.1l-.3 .3zM8.5 59.1v.6zM8.5 59.1h.6zM9.4 59.4v.6zM9.1 59.1l.3 .3zM9.7 41.5v35.7zM57.8 52v.7zM57.8 53.5v.7zM57.8 55v.8z"/>
<path d="M57.8 56.5v.8zM57.8 58v.8zM57.8 59.5v.8zM57.8 52h.8zM59.3 52h.8zM60.8 52h.8zM62.3 52h.8zM63.8 52h.8zM65.3 52h.8zM66.8 52h.8zM68.3 52h.8zM69.8 52h.8z"/>
<path d="M71.3 52h.8zM72.8 52h.8zM74.3 52h.8zM75.8 52h.8zM77.3 52h.8zM78.8 52h.8zM80.3 52h.8zM81.8 52h.8zM83.3 52h.8zM84.8 52h.8zM86.3 52h.8zM87.8 52h.8z"/>
<path d="M89.3 52h.8zM90.8 52h.8zM92.3 52h.8zM93.8 52h.8zM95.3 52h.8zM96.8 52h.8zM98.3 52h.8zM99.8 52h.8zM101.3 52h.8zM102.8 52h.8zM104.3 52h.8zM105.8 52h.8z"/>
<path d="M107.3 52h.8zM108.8 52h.8zM110.3 52h.8zM111.8 52h.8zM113.3 52h.8zM114.8 52h.8zM116.3 52h.8zM117.8 52h.8zM119.3 52h.8zM120.8 52h.8zM122.3 52h.8zM123.8 52h.8z"/>
<path d="M125.3 52h.8zM126.8 52h.8zM128.3 52h.8zM129.8 52h.8zM132.1 58v.8zM132.1 56.5v.8zM132.1 55v.8zM132.1 53.5v.7zM132.1 52v.7zM131.3 52h.8zM186.2 52.4v.3zM186.2 52.4h1.7z"/>
<path d="M186.8 53.3v.9zM186.8 54.2l.2 .3zM186.8 50.7v.6zM186.8 51.3l.2 .2zM186.8 48.6v.9zM186.8 49.5l.2 .3zM186.8 43.9v.6zM186.8 43.9l.2-.2zM186.8 43.1h.8zM186.8 40.4v.3zM187 54.5h.6zM187 50.4l-.2 .3z"/>
<path d="M187 51.5h.6zM187 49.8h.6zM187 45.4v1.2zM186.8 44.5l.2 .3zM187 43.7h.3zM186.8 47.2l.5 .8zM187.3 43.7v1.1zM186.8 40.7l.5 .6zM187.6 54.5l.3-.3zM187 50.4h.6zM187.6 51.5l.3-.2zM187.6 49.8l.3-.3z"/>
<path d="M187 44.8h.6zM187.6 43.1l.3-.3zM187.9 53.3v.9zM187.9 52.1v.6zM187.9 50.7v.6zM187.6 50.4l.3 .3zM187.9 48.6v.9zM186.2 48h1.7zM187.9 47.2l-.6 .8zM187.9 43.9v.6zM187.9 44.5l-.3 .3zM187.9 41.9v.9z"/>
<path d="M186.8 41.9h1.1zM186.8 41.3h1.1zM193.8 58.4l1.5-1.1zM193.8 51.3v.5zM193.8 51.8l.2 .3zM193.8 49.7v.5zM194 49.4l-.2 .3zM193.8 48.4h1.5zM193.8 46.8h1.5zM193.8 43.4v.5zM194 43.1l-.2 .3zM193.8 41.8v.5z"/>
<path d="M193.8 42.3l.2 .3zM194 51l-.2 .3zM193.8 50.2l.2 .3zM194 49.4h1.1zM193.8 43.9l.2 .3zM194 43.1h1.1zM194 41.5l-.2 .3zM193.8 40l.2 .2zM194.3 56v.5zM194.3 56.5l.3 .3zM194.3 55.2l1-.5zM194 51h.3z"/>
<path d="M193.8 48.4l.5 .5zM193.8 46.8l.5 .5zM194 41.5h.3zM194.3 40.7v.3zM194.3 40.7h.3zM194.6 55.7l-.3 .3zM194.6 56.8h.5zM194.6 40.7v.3zM194.3 41h.3zM194.6 55.7h.5zM195.3 56.5l-.2 .3zM194 50.5h1.1z"/>
<path d="M195.1 49.4l.2 .3zM194 49.4l1.1 1.1zM194 44.2h1.1zM195.1 43.1l.2 .3zM194 43.1l1.1 1.1zM195.1 40.7v.3zM195.1 40.7h.2zM194 40.2h1.1zM194 39.2l1.1 1zM193.8 58.4h1.5zM193.8 57.3h1.5zM195.3 56v.5z"/>
<path d="M195.1 55.7l.2 .3zM194.3 54.2l1 .5zM195.3 51v1.1zM194.3 51l1 1.1zM195.3 49.7v.5zM195.3 50.2l-.2 .3zM195.3 47.9v1zM195.3 46.3v1zM195.3 43.4v.5zM195.3 43.9l-.2 .3zM195.3 41.5v1.1zM194.3 41.5l1 1.1z"/>
<path d="M195.3 40.7v.3zM195.1 41h.2zM200.2 41.5v21.9zM200.2 41.5h2.4zM200.6 60v.6zM200.8 59.7l-.2 .3zM201.4 59.7v.6zM201.4 59.7h.6zM202 59.7l.3 .3zM202.6 3.4v38.1zM7.3 77.2v35.7zM7.3 77.2h2.4z"/>
<path d="M7.9 60.3h1.2zM9.1 60.3l.3-.3zM9.7 77.2v35.7zM57.8 61v.8zM57.8 62.5v.8zM57.8 64v.8zM57.8 65.6v.7zM57.8 67.1v.7zM57.8 68.6v.7zM57.8 70.1v.7zM57.8 71.6v.7zM57.8 73.1v.8z"/>
<path d="M57.8 74.6v.8zM57.8 76.1v.8zM57.8 77.6v.8zM57.8 79.1v.8zM65.4 61.5v5.7zM65.4 67.2v5.7zM67.3 61.5v5.7zM67.3 67.2v5.7zM69.2 61.5v5.7zM69.2 67.2v5.7zM71.1 61.5v5.7zM71.1 67.2v5.7z"/>
<path d="M73 61.5v5.7zM73 67.2v1.9zM74.9 61.5v5.7zM74.9 67.2v1.9zM76.9 61.5v5.7zM76.9 67.2v1.9zM78.8 61.5v5.7zM78.8 67.2v1.9zM80.7 61.5v5.7zM80.7 67.2v1.9zM82.6 61.5v5.7zM82.6 67.2v1.9z"/>
<path d="M84.5 61.5v5.7zM84.5 67.2v1.9zM86.4 61.5v5.7zM86.4 67.2v1.9zM88.3 61.5v5.7zM88.3 67.2v5.7zM90.2 61.5v5.7zM90.2 67.2v5.7zM92.1 61.5v5.7zM92.1 67.2v5.7zM94 61.5v5.7zM94 67.2v5.7z"/>
<path d="M95.9 61.5v5.7zM95.9 67.2v5.7zM97.8 61.5v5.7zM97.8 67.2v5.7zM99.7 61.5v5.7zM99.7 67.2v5.7zM101.6 61.5v5.7zM101.6 67.2v5.7zM103.5 61.5v5.7zM103.5 67.2v1.9zM105.4 61.5v5.7zM105.4 67.2v1.9z"/>
<path d="M107.3 61.5v5.7zM107.3 67.2v1.9zM109.2 61.5v5.7zM109.2 67.2v1.9zM111.1 61.5v5.7zM111.1 67.2v1.9zM113 61.5v5.7zM113 67.2v1.9zM115 61.5v5.7zM115 67.2v1.9zM116.9 61.5v5.7zM116.9 67.2v1.9z"/>
<path d="M118.8 61.5v5.7zM118.8 67.2v1.9zM120.7 61.5v5.7zM120.7 67.2v1.9zM122.6 61.5v5.7zM122.6 67.2v5.7zM124.5 61.5v5.7zM124.5 67.2v5.7zM132.1 79.1v.8zM132.1 77.6v.8zM132.1 76.1v.8zM132.1 74.6v.8z"/>
<path d="M132.1 73.1v.8zM132.1 71.6v.8zM132.1 70.1v.7zM132.1 68.6v.7zM132.1 67.1v.7zM132.1 65.6v.7zM132.1 64v.8zM132.1 62.5v.8zM132.1 61v.8zM132.1 59.5v.8zM188.8 5.8v57.6zM192.6 5.8v57.6z"/>
<path d="M193.8 60.7v.6zM193.8 61.3l.2 .2zM194 60.5l-.2 .2zM194 61.5h.3zM194.6 61.3l-.3 .2zM194.6 60.5v.8zM195.1 61.5l.2-.2zM194 60.5h1.1zM195.3 60.7v.6zM195.1 60.5l.2 .2zM200.2 63.4v13.8zM200.2 19.1v44.3z"/>
<path d="M200.2 77.2h2.4zM200.6 60.6l.2 .3zM200.8 60.9h1.2zM202.3 60.6l-.3 .3zM202.3 60v.6zM202.6 41.5v35.7zM7.6 95.5v1.2zM8.5 96.1v.6zM7.6 96.7h1.8zM57.8 92h.8zM57.8 80.6v.8zM57.8 82.2v.7z"/>
<path d="M57.8 83.7v.7zM57.8 85.2v.7zM57.8 86.7v.7zM57.8 88.2v.8zM57.8 89.7v.8zM57.8 91.2v.8zM59.3 92h.8zM60.8 92h.8zM62.3 92h.8zM63.8 92h.8zM65.3 92h.8zM66.8 92h.8z"/>
<path d="M68.3 92h.8zM69.8 92h.8zM71.3 92h.8zM72.8 92h.8zM74.3 92h.8zM75.8 92h.8zM77.3 92h.8zM78.8 92h.8zM80.3 92h.8zM81.8 92h.8zM83.3 92h.8zM84.8 92h.8z"/>
<path d="M86.3 92h.8zM87.8 92h.8zM89.3 92h.8zM90.8 92h.8zM92.3 92h.8zM93.8 92h.8zM95.3 92h.8zM96.8 92h.8zM98.3 92h.8zM99.8 92h.8zM101.3 92h.8zM102.8 92h.8z"/>
<path d="M104.3 92h.8zM105.8 92h.8zM107.3 92h.8zM108.8 92h.8zM110.3 92h.8zM111.8 92h.8zM113.3 92h.8zM114.8 92h.8zM116.3 92h.8zM117.8 92h.8zM119.3 92h.8zM120.8 92h.8z"/>
<path d="M122.3 92h.8zM123.8 92h.8zM125.3 92h.8zM126.8 92h.8zM128.3 92h.8zM129.8 92h.8zM131.3 92h.8zM132.1 91.2v.8zM132.1 89.7v.8zM132.1 88.2v.8zM132.1 86.7v.8zM132.1 85.2v.7z"/>
<path d="M132.1 83.7v.7zM132.1 82.2v.7zM132.1 80.6v.8zM200.6 94.9v1.2zM201.4 95.5v.6zM200.6 96.1h1.7zM7.3 112.9v35.8zM7.3 112.9h2.4zM9.7 112.9v35.8zM65.4 101.5v5.7zM65.4 107.2v5.7zM67.3 101.5v5.7z"/>
<path d="M67.3 107.2v5.7zM69.2 101.5v5.7zM69.2 107.2v5.7zM71.1 101.5v5.7zM71.1 107.2v5.7zM73 101.5v5.7zM73 107.2v5.7zM74.9 101.5v5.7zM74.9 107.2v5.7zM76.9 101.5v5.7zM76.9 107.2v5.7zM78.8 101.5v5.7z"/>
<path d="M78.8 107.2v5.7zM80.7 101.5v5.7zM80.7 107.2v5.7zM82.6 101.5v5.7zM82.6 107.2v5.7zM84.5 101.5v5.7zM84.5 107.2v5.7zM86.4 101.5v5.7zM86.4 107.2v5.7zM88.3 101.5v5.7zM88.3 107.2v5.7zM90.2 101.5v5.7z"/>
<path d="M90.2 107.2v5.7zM92.1 101.5v5.7zM92.1 107.2v5.7zM94 101.5v5.7zM94 107.2v5.7zM95.9 101.5v5.7zM95.9 107.2v5.7zM97.8 101.5v5.7zM97.8 107.2v5.7zM99.7 101.5v5.7zM99.7 107.2v5.7zM101.6 101.5v5.7z"/>
<path d="M101.6 107.2v5.7zM103.5 101.5v5.7zM103.5 107.2v5.7zM105.4 101.5v5.7zM105.4 107.2v5.7zM107.3 101.5v5.7zM107.3 107.2v5.7zM109.2 101.5v5.7zM109.2 107.2v5.7zM111.1 101.5v5.7zM111.1 107.2v5.7zM113 101.5v5.7z"/>
<path d="M113 107.2v5.7zM115 101.5v5.7zM115 107.2v5.7zM116.9 101.5v5.7zM116.9 107.2v5.7zM118.8 101.5v5.7zM118.8 107.2v5.7zM120.7 101.5v5.7zM120.7 107.2v5.7zM122.6 101.5v5.7zM122.6 107.2v5.7zM124.5 101.5v5.7z"/>
<path d="M124.5 107.2v5.7zM200.2 77.2v35.7zM200.2 112.9h2.4zM202.6 77.2v35.7zM7.6 130.7v1.2zM7.6 131.9h1.8zM8.5 131.3v.6zM9.4 130.7v1.2zM200.6 130v1.1zM200.6 131.1h1.7zM201.4 130.6v.5zM202.3 130v1.1z"/>
<path d="M7.3 148.7v35.7zM7.3 148.7h2.4zM9.7 148.7v35.7zM200.2 112.9v35.8zM200.2 148.7h2.4zM202.6 112.9v35.8zM7.6 167.7h1.8zM7.6 166.8v.9zM7.9 166.5l-.3 .3zM7.9 166.5h1.2zM9.4 166.8v.9zM9.1 166.5l.3 .3z"/>
<path d="M65.4 170.1v5.7zM65.4 175.8v5.7zM67.3 170.1v5.7zM67.3 175.8v5.7zM69.2 170.1v5.7zM69.2 175.8v5.7zM71.1 170.1v5.7zM71.1 175.8v5.7zM73 170.1v5.7zM73 175.8v5.7zM74.9 170.1v5.7zM74.9 175.8v5.7z"/>
<path d="M76.9 170.1v5.7zM76.9 175.8v5.7zM78.8 170.1v5.7zM78.8 175.8v5.7zM80.7 170.1v5.7zM80.7 175.8v5.7zM82.6 170.1v5.7zM82.6 175.8v5.7zM84.5 170.1v5.7zM84.5 175.8v5.7zM86.4 170.1v5.7zM86.4 175.8v5.7z"/>
<path d="M88.3 170.1v5.7zM88.3 175.8v5.7zM90.2 170.1v5.7zM90.2 175.8v5.7zM92.1 170.1v5.7zM92.1 175.8v5.7zM94 170.1v5.7zM94 175.8v5.7zM95.9 170.1v5.7zM95.9 175.8v5.7zM97.8 170.1v5.7zM97.8 175.8v5.7z"/>
<path d="M99.7 170.1v5.7zM99.7 175.8v5.7zM101.6 170.1v5.7zM103.5 170.1v5.7zM105.4 170.1v5.7zM107.3 170.1v5.7zM109.2 170.1v5.7zM109.2 175.8v5.7zM111.1 170.1v5.7zM113 170.1v5.7zM115 170.1v5.7zM116.9 170.1v5.7z"/>
<path d="M118.8 170.1v5.7zM120.7 170.1v5.7zM120.7 175.8v5.7zM122.6 170.1v5.7zM122.6 175.8v5.7zM124.5 170.1v5.7zM124.5 175.8v5.7zM200.6 166.7h1.7zM200.6 165.9v.8zM200.8 165.6l-.2 .3zM200.8 165.6h1.2zM202.3 165.9v.8z"/>
<path d="M202 165.6l.3 .3zM7.3 184.4v35.7zM9.7 184.4v35.7zM7.3 184.4h2.4zM101.6 175.8v5.7zM103.5 175.8v5.7zM105.4 175.8v5.7zM107.3 175.8v5.7zM111.1 175.8v5.7zM113 175.8v5.7zM115 175.8v5.7zM116.9 175.8v5.7z"/>
<path d="M118.8 175.8v5.7zM200.2 148.7v35.7zM200.2 184.4h2.4zM202.6 148.7v35.7zM7.6 202.3v.5zM7.6 202.8l.3 .3zM7.9 202l-.3 .3zM7.9 203.1h1.2zM9.1 203.1l.3-.3zM9.4 202.3v.5zM9.1 202l.3 .3zM65.4 210.1v5.7z"/>
<path d="M65.4 215.8v5.7zM67.3 210.1v5.7zM67.3 215.8v5.7zM69.2 210.1v5.7zM69.2 215.8v5.7zM71.1 210.1v5.7zM71.1 215.8v5.7zM73 210.1v5.7zM74.9 210.1v5.7zM76.9 210.1v5.7zM78.8 210.1v5.7zM80.7 210.1v5.7z"/>
<path d="M82.6 210.1v5.7zM84.5 210.1v5.7zM86.4 210.1v5.7zM88.3 210.1v5.7zM88.3 215.8v5.7zM90.2 210.1v5.7zM92.1 210.1v5.7zM94 210.1v5.7zM95.9 210.1v5.7zM97.8 210.1v5.7zM99.7 210.1v5.7zM101.6 210.1v5.7z"/>
<path d="M103.5 210.1v5.7zM105.4 210.1v5.7zM107.3 210.1v5.7zM109.2 210.1v5.7zM111.1 210.1v5.7zM113 210.1v5.7zM115 210.1v5.7zM116.9 210.1v5.7zM116.9 215.8v5.7zM118.8 210.1v5.7zM120.7 210.1v5.7zM120.7 215.8v5.7z"/>
<path d="M122.6 210.1v5.7zM122.6 215.8v5.7zM124.5 210.1v5.7zM124.5 215.8v5.7zM200.6 202.1v.5zM200.6 202.6l.2 .3zM200.8 201.8l-.2 .3zM200.8 202.9h1.2zM202.3 202.6l-.3 .3zM202.3 202.1v.5zM202 201.8l.3 .3zM7.3 220.1v35.7z"/>
<path d="M7.6 238.2v.9zM7.6 238.2l.3-.2zM7.9 238h.3zM8.2 238l.3 .2zM8.8 238l-.3 .2zM8.5 238.2v.9zM8.8 238h.3zM9.1 238l.3 .2zM7.6 239.1h1.8zM9.4 238.2v.9zM9.7 220.1v35.7zM7.3 220.1h2.4z"/>
<path d="M73 215.8v5.7zM74.9 215.8v5.7zM76.9 215.8v5.7zM78.8 215.8v5.7zM80.7 215.8v5.7zM82.6 215.8v5.7zM84.5 215.8v5.7zM86.4 215.8v5.7zM90.2 215.8v5.7zM92.1 215.8v5.7zM94 215.8v5.7zM95.9 215.8v5.7z"/>
<path d="M97.8 215.8v5.7zM99.7 215.8v5.7zM101.6 215.8v5.7zM103.5 215.8v5.7zM105.4 215.8v5.7zM107.3 215.8v5.7zM109.2 215.8v5.7zM111.1 215.8v5.7zM113 215.8v5.7zM115 215.8v5.7zM118.8 215.8v5.7zM200.2 184.4v35.7z"/>
<path d="M200.2 220.1h2.4zM200.6 237.1v.9zM200.6 237.1l.2-.3zM200.8 236.8h.3zM201.1 236.8l.3 .3zM201.4 237.1l.3-.3zM201.4 237.1v.9zM201.7 236.8h.3zM202 236.8l.3 .3zM200.6 238h1.7zM202.3 237.1v.9zM202.6 184.4v35.7z"/>
<path d="M7.3 255.8v38.1zM9.7 255.8v35.7zM7.3 255.8h2.4zM65.4 250.1v5.7zM65.4 255.8v5.7zM67.3 250.1v5.7zM67.3 255.8v5.7zM69.2 250.1v5.7zM69.2 255.8v5.7zM71.1 250.1v5.7zM71.1 255.8v5.7zM73 250.1v5.7z"/>
<path d="M73 255.8v1.9zM74.9 250.1v5.7zM74.9 255.8v1.9zM76.9 250.1v5.7zM76.9 255.8v1.9zM78.8 250.1v5.7zM78.8 255.8v1.9zM80.7 250.1v5.7zM82.6 250.1v5.7zM82.6 255.8v5.7zM84.5 250.1v5.7zM84.5 255.8v5.7z"/>
<path d="M86.4 250.1v5.7zM88.3 250.1v5.7zM90.2 250.1v5.7zM92.1 250.1v5.7zM94 250.1v5.7zM94 255.8v5.7zM95.9 250.1v5.7zM95.9 255.8v5.7zM97.8 250.1v5.7zM99.7 250.1v5.7zM101.6 250.1v5.7zM103.5 250.1v5.7z"/>
<path d="M105.4 250.1v5.7zM107.3 250.1v5.7zM109.2 250.1v5.7zM111.1 250.1v5.7zM111.1 255.8v5.7zM113 250.1v5.7zM115 250.1v5.7zM116.9 250.1v5.7zM118.8 250.1v5.7zM118.8 255.8v5.7zM120.7 250.1v5.7zM120.7 255.8v5.7z"/>
<path d="M122.6 250.1v5.7zM122.6 255.8v5.7zM124.5 250.1v5.7zM124.5 255.8v5.7zM200.2 220.1v35.7zM202.6 220.1v35.7zM200.2 255.8h2.4zM7.6 274.9l.6-.6zM7.6 274.9l.6 .6zM8.2 274.3h1.2zM8.5 274.3v1.2zM8.2 275.5h1.2z"/>
<path d="M80.7 255.8v5.7zM86.4 255.8v5.7zM88.3 255.8v5.7zM90.2 255.8v5.7zM92.1 255.8v5.7zM97.8 255.8v5.7zM99.7 255.8v5.7zM101.6 255.8v5.7zM103.5 255.8v5.7zM105.4 255.8v5.7zM107.3 255.8v5.7zM109.2 255.8v5.7z"/>
<path d="M113 255.8v5.7zM115 255.8v5.7zM116.9 255.8v5.7zM201.1 274.3l-.5 .6zM200.6 274.9l.5 .6zM201.1 274.3h1.2zM201.4 274.3v1.2zM201.1 275.5h1.2zM7.3 293.9h40.5zM9.7 291.5h38.1zM27.4 292.1v1.1zM27.4 293.2h.9z"/>
<path d="M28 292.3v.3zM28.3 292.1l-.3 .2zM28 292.6l.3 .6zM28.3 292.1h.6zM28.9 292.1l.3 .2zM29.2 292.3v.6zM28.9 293.2l.3-.3zM47.8 293.9h38.1zM47.8 291.5h38.1zM47.8 291.5v2.4zM64.6 292.3l.8 .9zM65.4 292.1v1.1z"/>
<path d="M64.6 292.3h1.7zM85.9 293.9h38.1zM85.9 291.5h38.1zM85.9 291.5v2.4zM103 292.3v.6zM103 292.3l.3-.2zM103 292.9l.3 .3zM103.3 292.1h.3zM103.6 292.1l.3 .2zM103.9 292.3v.3zM103.9 292.3l.3-.2zM104.2 292.1h.3z"/>
<path d="M104.5 292.1l.3 .2zM104.8 292.3v.6zM104.5 293.2l.3-.3zM124 293.9h38.1zM124 291.5h38.1zM124 291.5v2.4zM141.3 292.3v.6zM141.3 292.9l.3 .3zM141.6 292.1l-.3 .2zM141.6 292.1h.3zM143.1 292.1v1.1zM141.9 292.1l1.2 1.1z"/>
<path d="M162.1 293.9h40.5zM162.1 291.5h38.1zM162.1 291.5v2.4zM180.7 292.5h1.8zM180.7 292.5l.6 .5zM182.5 291.9v1.1zM200.2 255.8v35.7zM202.6 255.8v38.1z"/>
</g>
<g fill="#000" stroke="#000" stroke-width=".47">
<path d="M65.4 20.6v.9zM67.3 20.6v.9zM69.2 20.6v.9zM71.1 20.6v.9zM73 20.6v.9zM74.9 20.6v.9zM76.9 20.6v.9zM78.8 20.6v.9zM80.7 20.6v.9zM82.6 20.6v.9zM84.5 20.6v.9zM86.4 20.6v.9z"/>
<path d="M88.3 20.6v.9zM90.2 20.6v.9zM92.1 20.6v.9zM94 20.6v.9zM95.9 20.6v.9zM97.8 20.6v.9zM99.7 20.6v.9zM101.6 20.6v.9zM103.5 20.6v.9zM105.4 20.6v.9zM107.3 20.6v.9zM109.2 20.6v.9z"/>
<path d="M111.1 20.6v.9zM113 20.6v.9zM115 20.6v.9zM116.9 20.6v.9zM118.8 20.6v.9zM120.7 20.6v.9zM122.6 20.6v.9zM124.5 20.6v.9zM65.4 60.6v.9zM67.3 60.6v.9zM69.2 60.6v.9zM71.1 60.6v.9z"/>
<path d="M73 60.6v.9zM74.9 60.6v.9zM76.9 60.6v.9zM78.8 60.6v.9zM80.7 60.6v.9zM82.6 60.6v.9zM84.5 60.6v.9zM86.4 60.6v.9zM88.3 60.6v.9zM90.2 60.6v.9zM92.1 60.6v.9zM94 60.6v.9z"/>
<path d="M95.9 60.6v.9zM97.8 60.6v.9zM99.7 60.6v.9zM101.6 60.6v.9zM103.5 60.6v.9zM105.4 60.6v.9zM107.3 60.6v.9zM109.2 60.6v.9zM111.1 60.6v.9zM113 60.6v.9zM115 60.6v.9zM116.9 60.6v.9z"/>
<path d="M118.8 60.6v.9zM120.7 60.6v.9zM122.6 60.6v.9zM124.5 60.6v.9zM185 63.4v13.8zM185 5.8v57.6zM185 63.4h3.8zM188.8 63.4h3.8zM196.4 63.4h3.8zM192.6 63.4h3.8zM185 77.2h15.2zM65.4 100.5v1z"/>
<path d="M67.3 100.5v1zM69.2 100.5v1zM71.1 100.5v1zM73 100.5v1zM74.9 100.5v1zM76.9 100.5v1zM78.8 100.5v1zM80.7 100.5v1zM82.6 100.5v1zM84.5 100.5v1zM86.4 100.5v1zM88.3 100.5v1z"/>
<path d="M90.2 100.5v1zM92.1 100.5v1zM94 100.5v1zM95.9 100.5v1zM97.8 100.5v1zM99.7 100.5v1zM101.6 100.5v1zM103.5 100.5v1zM105.4 100.5v1zM107.3 100.5v1zM109.2 100.5v1zM111.1 100.5v1z"/>
<path d="M113 100.5v1zM115 100.5v1zM116.9 100.5v1zM118.8 100.5v1zM120.7 100.5v1zM122.6 100.5v1zM124.5 100.5v1zM65.4 169.1v1zM67.3 169.1v1zM69.2 169.1v1zM71.1 169.1v1zM73 169.1v1z"/>
<path d="M74.9 169.1v1zM76.9 169.1v1zM78.8 169.1v1zM80.7 169.1v1zM82.6 169.1v1zM84.5 169.1v1zM86.4 169.1v1zM88.3 169.1v1zM90.2 169.1v1zM92.1 169.1v1zM94 169.1v1zM95.9 169.1v1z"/>
<path d="M97.8 169.1v1zM99.7 169.1v1zM101.6 169.1v1zM103.5 169.1v1zM105.4 169.1v1zM107.3 169.1v1zM109.2 169.1v1zM111.1 169.1v1zM113 169.1v1zM115 169.1v1zM116.9 169.1v1zM118.8 169.1v1z"/>
<path d="M120.7 169.1v1zM122.6 169.1v1zM124.5 169.1v1zM65.4 209.1v1zM67.3 209.1v1zM69.2 209.1v1zM71.1 209.1v1zM73 209.1v1zM74.9 209.1v1zM76.9 209.1v1zM78.8 209.1v1zM80.7 209.1v1z"/>
<path d="M82.6 209.1v1zM84.5 209.1v1zM86.4 209.1v1zM88.3 209.1v1zM90.2 209.1v1zM92.1 209.1v1zM94 209.1v1zM95.9 209.1v1zM97.8 209.1v1zM99.7 209.1v1zM101.6 209.1v1zM103.5 209.1v1z"/>
<path d="M105.4 209.1v1zM107.3 209.1v1zM109.2 209.1v1zM111.1 209.1v1zM113 209.1v1zM115 209.1v1zM116.9 209.1v1zM118.8 209.1v1zM120.7 209.1v1zM122.6 209.1v1zM124.5 209.1v1zM65.4 249.1v1z"/>
<path d="M67.3 249.1v1zM69.2 249.1v1zM71.1 249.1v1zM73 249.1v1zM74.9 249.1v1zM76.9 249.1v1zM78.8 249.1v1zM80.7 249.1v1zM82.6 249.1v1zM84.5 249.1v1zM86.4 249.1v1zM88.3 249.1v1z"/>
<path d="M90.2 249.1v1zM92.1 249.1v1zM94 249.1v1zM95.9 249.1v1zM97.8 249.1v1zM99.7 249.1v1zM101.6 249.1v1zM103.5 249.1v1zM105.4 249.1v1zM107.3 249.1v1zM109.2 249.1v1zM111.1 249.1v1z"/>
<path d="M113 249.1v1zM115 249.1v1zM116.9 249.1v1zM118.8 249.1v1zM120.7 249.1v1zM122.6 249.1v1zM124.5 249.1v1z"/>
</g>
<g fill="#000" stroke="#000" stroke-width=".32">
<path d="M63.5 18.6h62.9zM63.5 18.6v3.9zM126.4 18.6v3.9zM63.5 22.5h62.9zM63.5 58.7h62.9zM63.5 58.7v3.8zM126.4 58.7v3.8zM63.5 62.5h62.9zM63.5 98.6h62.9zM63.5 98.6v3.8zM126.4 98.6v3.8zM63.5 102.4h62.9z"/>
<path d="M63.5 167.2h62.9zM63.5 167.2v3.8zM126.4 167.2v3.8zM63.5 171h62.9zM63.5 207.2h62.9zM63.5 207.2v3.8zM126.4 207.2v3.8zM63.5 211h62.9zM63.5 247.2h62.9zM63.5 247.2v3.8zM126.4 247.2v3.8zM63.5 251h62.9z"/>
</g>
<use href="#words"/>
</svg>
